VERSION 5.8 ;
BUSBITCHARS "[]" ;
DIVIDERCHAR "/" ;
UNITS
    DATABASE MICRONS 1000 ;
END UNITS

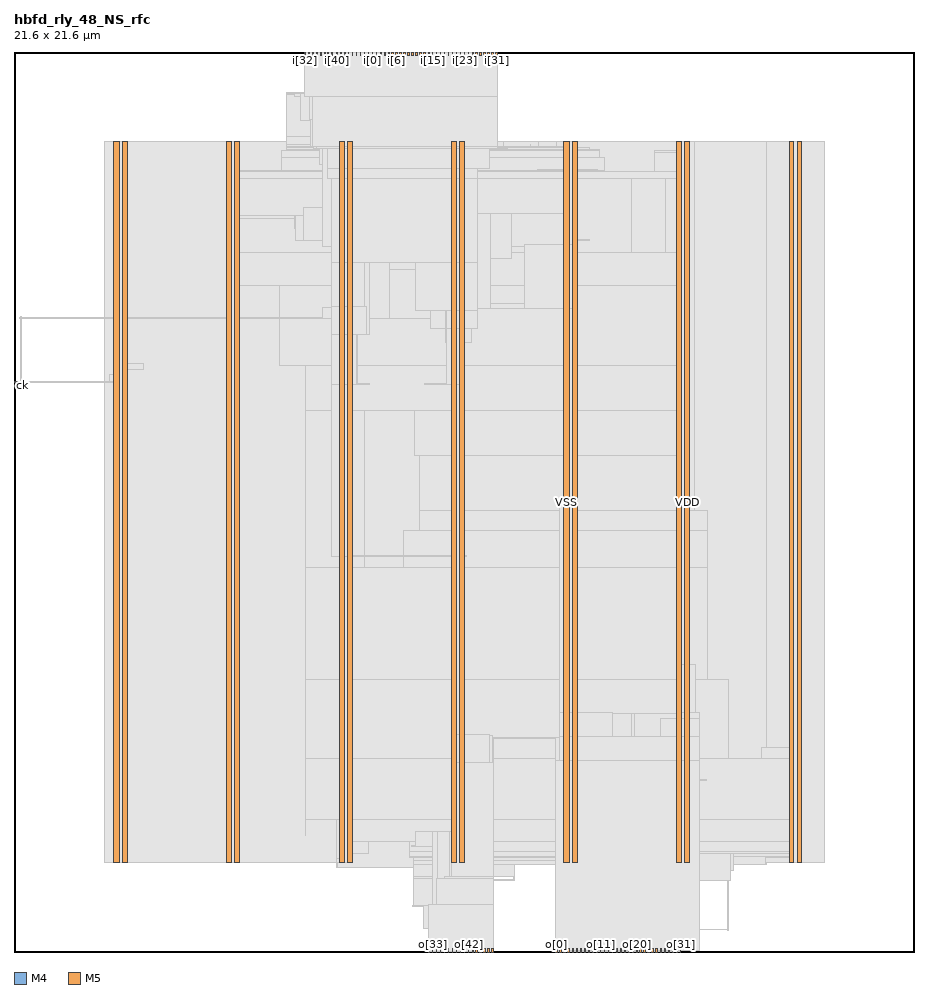
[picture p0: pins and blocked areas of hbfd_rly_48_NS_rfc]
MACRO hbfd_rly_48_NS_rfc
  FOREIGN hbfd_rly_48_NS_rfc 0 0 ;
  CLASS BLOCK ;
  SIZE 21.6 BY 21.6 ;
  PIN ck
    DIRECTION INPUT ;
    USE SIGNAL ;
    PORT
      LAYER M4 ;
        RECT  0 13.584 0.084 13.608 ;
    END
  END ck
  PIN i[0]
    DIRECTION INPUT ;
    USE SIGNAL ;
    PORT
      LAYER M5 ;
        RECT  8.592 21.516 8.616 21.6 ;
    END
  END i[0]
  PIN i[10]
    DIRECTION INPUT ;
    USE SIGNAL ;
    PORT
      LAYER M5 ;
        RECT  9.552 21.516 9.576 21.6 ;
    END
  END i[10]
  PIN i[11]
    DIRECTION INPUT ;
    USE SIGNAL ;
    PORT
      LAYER M5 ;
        RECT  9.648 21.516 9.672 21.6 ;
    END
  END i[11]
  PIN i[12]
    DIRECTION INPUT ;
    USE SIGNAL ;
    PORT
      LAYER M5 ;
        RECT  9.744 21.516 9.768 21.6 ;
    END
  END i[12]
  PIN i[13]
    DIRECTION INPUT ;
    USE SIGNAL ;
    PORT
      LAYER M5 ;
        RECT  9.84 21.516 9.864 21.6 ;
    END
  END i[13]
  PIN i[14]
    DIRECTION INPUT ;
    USE SIGNAL ;
    PORT
      LAYER M5 ;
        RECT  9.936 21.516 9.96 21.6 ;
    END
  END i[14]
  PIN i[15]
    DIRECTION INPUT ;
    USE SIGNAL ;
    PORT
      LAYER M5 ;
        RECT  10.032 21.516 10.056 21.6 ;
    END
  END i[15]
  PIN i[16]
    DIRECTION INPUT ;
    USE SIGNAL ;
    PORT
      LAYER M5 ;
        RECT  10.128 21.516 10.152 21.6 ;
    END
  END i[16]
  PIN i[17]
    DIRECTION INPUT ;
    USE SIGNAL ;
    PORT
      LAYER M5 ;
        RECT  10.224 21.516 10.248 21.6 ;
    END
  END i[17]
  PIN i[18]
    DIRECTION INPUT ;
    USE SIGNAL ;
    PORT
      LAYER M5 ;
        RECT  10.32 21.516 10.344 21.6 ;
    END
  END i[18]
  PIN i[19]
    DIRECTION INPUT ;
    USE SIGNAL ;
    PORT
      LAYER M5 ;
        RECT  10.416 21.516 10.44 21.6 ;
    END
  END i[19]
  PIN i[1]
    DIRECTION INPUT ;
    USE SIGNAL ;
    PORT
      LAYER M5 ;
        RECT  8.688 21.516 8.712 21.6 ;
    END
  END i[1]
  PIN i[20]
    DIRECTION INPUT ;
    USE SIGNAL ;
    PORT
      LAYER M5 ;
        RECT  10.512 21.516 10.536 21.6 ;
    END
  END i[20]
  PIN i[21]
    DIRECTION INPUT ;
    USE SIGNAL ;
    PORT
      LAYER M5 ;
        RECT  10.608 21.516 10.632 21.6 ;
    END
  END i[21]
  PIN i[22]
    DIRECTION INPUT ;
    USE SIGNAL ;
    PORT
      LAYER M5 ;
        RECT  10.704 21.516 10.728 21.6 ;
    END
  END i[22]
  PIN i[23]
    DIRECTION INPUT ;
    USE SIGNAL ;
    PORT
      LAYER M5 ;
        RECT  10.8 21.516 10.824 21.6 ;
    END
  END i[23]
  PIN i[24]
    DIRECTION INPUT ;
    USE SIGNAL ;
    PORT
      LAYER M5 ;
        RECT  10.896 21.516 10.92 21.6 ;
    END
  END i[24]
  PIN i[25]
    DIRECTION INPUT ;
    USE SIGNAL ;
    PORT
      LAYER M5 ;
        RECT  10.992 21.516 11.016 21.6 ;
    END
  END i[25]
  PIN i[26]
    DIRECTION INPUT ;
    USE SIGNAL ;
    PORT
      LAYER M5 ;
        RECT  11.088 21.516 11.112 21.6 ;
    END
  END i[26]
  PIN i[27]
    DIRECTION INPUT ;
    USE SIGNAL ;
    PORT
      LAYER M5 ;
        RECT  11.184 21.516 11.208 21.6 ;
    END
  END i[27]
  PIN i[28]
    DIRECTION INPUT ;
    USE SIGNAL ;
    PORT
      LAYER M5 ;
        RECT  11.28 21.516 11.304 21.6 ;
    END
  END i[28]
  PIN i[29]
    DIRECTION INPUT ;
    USE SIGNAL ;
    PORT
      LAYER M5 ;
        RECT  11.376 21.516 11.4 21.6 ;
    END
  END i[29]
  PIN i[2]
    DIRECTION INPUT ;
    USE SIGNAL ;
    PORT
      LAYER M5 ;
        RECT  8.784 21.516 8.808 21.6 ;
    END
  END i[2]
  PIN i[30]
    DIRECTION INPUT ;
    USE SIGNAL ;
    PORT
      LAYER M5 ;
        RECT  11.472 21.516 11.496 21.6 ;
    END
  END i[30]
  PIN i[31]
    DIRECTION INPUT ;
    USE SIGNAL ;
    PORT
      LAYER M5 ;
        RECT  11.568 21.516 11.592 21.6 ;
    END
  END i[31]
  PIN i[32]
    DIRECTION INPUT ;
    USE SIGNAL ;
    PORT
      LAYER M5 ;
        RECT  6.96 21.516 6.984 21.6 ;
    END
  END i[32]
  PIN i[33]
    DIRECTION INPUT ;
    USE SIGNAL ;
    PORT
      LAYER M5 ;
        RECT  7.056 21.516 7.08 21.6 ;
    END
  END i[33]
  PIN i[34]
    DIRECTION INPUT ;
    USE SIGNAL ;
    PORT
      LAYER M5 ;
        RECT  7.152 21.516 7.176 21.6 ;
    END
  END i[34]
  PIN i[35]
    DIRECTION INPUT ;
    USE SIGNAL ;
    PORT
      LAYER M5 ;
        RECT  7.248 21.516 7.272 21.6 ;
    END
  END i[35]
  PIN i[36]
    DIRECTION INPUT ;
    USE SIGNAL ;
    PORT
      LAYER M5 ;
        RECT  7.344 21.516 7.368 21.6 ;
    END
  END i[36]
  PIN i[37]
    DIRECTION INPUT ;
    USE SIGNAL ;
    PORT
      LAYER M5 ;
        RECT  7.44 21.516 7.464 21.6 ;
    END
  END i[37]
  PIN i[38]
    DIRECTION INPUT ;
    USE SIGNAL ;
    PORT
      LAYER M5 ;
        RECT  7.536 21.516 7.56 21.6 ;
    END
  END i[38]
  PIN i[39]
    DIRECTION INPUT ;
    USE SIGNAL ;
    PORT
      LAYER M5 ;
        RECT  7.632 21.516 7.656 21.6 ;
    END
  END i[39]
  PIN i[3]
    DIRECTION INPUT ;
    USE SIGNAL ;
    PORT
      LAYER M5 ;
        RECT  8.88 21.516 8.904 21.6 ;
    END
  END i[3]
  PIN i[40]
    DIRECTION INPUT ;
    USE SIGNAL ;
    PORT
      LAYER M5 ;
        RECT  7.728 21.516 7.752 21.6 ;
    END
  END i[40]
  PIN i[41]
    DIRECTION INPUT ;
    USE SIGNAL ;
    PORT
      LAYER M5 ;
        RECT  7.824 21.516 7.848 21.6 ;
    END
  END i[41]
  PIN i[42]
    DIRECTION INPUT ;
    USE SIGNAL ;
    PORT
      LAYER M5 ;
        RECT  7.92 21.516 7.944 21.6 ;
    END
  END i[42]
  PIN i[43]
    DIRECTION INPUT ;
    USE SIGNAL ;
    PORT
      LAYER M5 ;
        RECT  8.016 21.516 8.04 21.6 ;
    END
  END i[43]
  PIN i[44]
    DIRECTION INPUT ;
    USE SIGNAL ;
    PORT
      LAYER M5 ;
        RECT  8.112 21.516 8.136 21.6 ;
    END
  END i[44]
  PIN i[45]
    DIRECTION INPUT ;
    USE SIGNAL ;
    PORT
      LAYER M5 ;
        RECT  8.208 21.516 8.232 21.6 ;
    END
  END i[45]
  PIN i[46]
    DIRECTION INPUT ;
    USE SIGNAL ;
    PORT
      LAYER M5 ;
        RECT  8.304 21.516 8.328 21.6 ;
    END
  END i[46]
  PIN i[47]
    DIRECTION INPUT ;
    USE SIGNAL ;
    PORT
      LAYER M5 ;
        RECT  8.4 21.516 8.424 21.6 ;
    END
  END i[47]
  PIN i[4]
    DIRECTION INPUT ;
    USE SIGNAL ;
    PORT
      LAYER M5 ;
        RECT  8.976 21.516 9 21.6 ;
    END
  END i[4]
  PIN i[5]
    DIRECTION INPUT ;
    USE SIGNAL ;
    PORT
      LAYER M5 ;
        RECT  9.072 21.516 9.096 21.6 ;
    END
  END i[5]
  PIN i[6]
    DIRECTION INPUT ;
    USE SIGNAL ;
    PORT
      LAYER M5 ;
        RECT  9.168 21.516 9.192 21.6 ;
    END
  END i[6]
  PIN i[7]
    DIRECTION INPUT ;
    USE SIGNAL ;
    PORT
      LAYER M5 ;
        RECT  9.264 21.516 9.288 21.6 ;
    END
  END i[7]
  PIN i[8]
    DIRECTION INPUT ;
    USE SIGNAL ;
    PORT
      LAYER M5 ;
        RECT  9.36 21.516 9.384 21.6 ;
    END
  END i[8]
  PIN i[9]
    DIRECTION INPUT ;
    USE SIGNAL ;
    PORT
      LAYER M5 ;
        RECT  9.456 21.516 9.48 21.6 ;
    END
  END i[9]
  PIN o[0]
    DIRECTION OUTPUT ;
    USE SIGNAL ;
    PORT
      LAYER M5 ;
        RECT  13.008 0 13.032 0.084 ;
    END
  END o[0]
  PIN o[10]
    DIRECTION OUTPUT ;
    USE SIGNAL ;
    PORT
      LAYER M5 ;
        RECT  13.968 0 13.992 0.084 ;
    END
  END o[10]
  PIN o[11]
    DIRECTION OUTPUT ;
    USE SIGNAL ;
    PORT
      LAYER M5 ;
        RECT  14.064 0 14.088 0.084 ;
    END
  END o[11]
  PIN o[12]
    DIRECTION OUTPUT ;
    USE SIGNAL ;
    PORT
      LAYER M5 ;
        RECT  14.16 0 14.184 0.084 ;
    END
  END o[12]
  PIN o[13]
    DIRECTION OUTPUT ;
    USE SIGNAL ;
    PORT
      LAYER M5 ;
        RECT  14.256 0 14.28 0.084 ;
    END
  END o[13]
  PIN o[14]
    DIRECTION OUTPUT ;
    USE SIGNAL ;
    PORT
      LAYER M5 ;
        RECT  14.352 0 14.376 0.084 ;
    END
  END o[14]
  PIN o[15]
    DIRECTION OUTPUT ;
    USE SIGNAL ;
    PORT
      LAYER M5 ;
        RECT  14.448 0 14.472 0.084 ;
    END
  END o[15]
  PIN o[16]
    DIRECTION OUTPUT ;
    USE SIGNAL ;
    PORT
      LAYER M5 ;
        RECT  14.544 0 14.568 0.084 ;
    END
  END o[16]
  PIN o[17]
    DIRECTION OUTPUT ;
    USE SIGNAL ;
    PORT
      LAYER M5 ;
        RECT  14.64 0 14.664 0.084 ;
    END
  END o[17]
  PIN o[18]
    DIRECTION OUTPUT ;
    USE SIGNAL ;
    PORT
      LAYER M5 ;
        RECT  14.736 0 14.76 0.084 ;
    END
  END o[18]
  PIN o[19]
    DIRECTION OUTPUT ;
    USE SIGNAL ;
    PORT
      LAYER M5 ;
        RECT  14.832 0 14.856 0.084 ;
    END
  END o[19]
  PIN o[1]
    DIRECTION OUTPUT ;
    USE SIGNAL ;
    PORT
      LAYER M5 ;
        RECT  13.104 0 13.128 0.084 ;
    END
  END o[1]
  PIN o[20]
    DIRECTION OUTPUT ;
    USE SIGNAL ;
    PORT
      LAYER M5 ;
        RECT  14.928 0 14.952 0.084 ;
    END
  END o[20]
  PIN o[21]
    DIRECTION OUTPUT ;
    USE SIGNAL ;
    PORT
      LAYER M5 ;
        RECT  15.024 0 15.048 0.084 ;
    END
  END o[21]
  PIN o[22]
    DIRECTION OUTPUT ;
    USE SIGNAL ;
    PORT
      LAYER M5 ;
        RECT  15.12 0 15.144 0.084 ;
    END
  END o[22]
  PIN o[23]
    DIRECTION OUTPUT ;
    USE SIGNAL ;
    PORT
      LAYER M5 ;
        RECT  15.216 0 15.24 0.084 ;
    END
  END o[23]
  PIN o[24]
    DIRECTION OUTPUT ;
    USE SIGNAL ;
    PORT
      LAYER M5 ;
        RECT  15.312 0 15.336 0.084 ;
    END
  END o[24]
  PIN o[25]
    DIRECTION OUTPUT ;
    USE SIGNAL ;
    PORT
      LAYER M5 ;
        RECT  15.408 0 15.432 0.084 ;
    END
  END o[25]
  PIN o[26]
    DIRECTION OUTPUT ;
    USE SIGNAL ;
    PORT
      LAYER M5 ;
        RECT  15.504 0 15.528 0.084 ;
    END
  END o[26]
  PIN o[27]
    DIRECTION OUTPUT ;
    USE SIGNAL ;
    PORT
      LAYER M5 ;
        RECT  15.6 0 15.624 0.084 ;
    END
  END o[27]
  PIN o[28]
    DIRECTION OUTPUT ;
    USE SIGNAL ;
    PORT
      LAYER M5 ;
        RECT  15.696 0 15.72 0.084 ;
    END
  END o[28]
  PIN o[29]
    DIRECTION OUTPUT ;
    USE SIGNAL ;
    PORT
      LAYER M5 ;
        RECT  15.792 0 15.816 0.084 ;
    END
  END o[29]
  PIN o[2]
    DIRECTION OUTPUT ;
    USE SIGNAL ;
    PORT
      LAYER M5 ;
        RECT  13.2 0 13.224 0.084 ;
    END
  END o[2]
  PIN o[30]
    DIRECTION OUTPUT ;
    USE SIGNAL ;
    PORT
      LAYER M5 ;
        RECT  15.888 0 15.912 0.084 ;
    END
  END o[30]
  PIN o[31]
    DIRECTION OUTPUT ;
    USE SIGNAL ;
    PORT
      LAYER M5 ;
        RECT  15.984 0 16.008 0.084 ;
    END
  END o[31]
  PIN o[32]
    DIRECTION OUTPUT ;
    USE SIGNAL ;
    PORT
      LAYER M5 ;
        RECT  9.936 0 9.96 0.084 ;
    END
  END o[32]
  PIN o[33]
    DIRECTION OUTPUT ;
    USE SIGNAL ;
    PORT
      LAYER M5 ;
        RECT  10.032 0 10.056 0.084 ;
    END
  END o[33]
  PIN o[34]
    DIRECTION OUTPUT ;
    USE SIGNAL ;
    PORT
      LAYER M5 ;
        RECT  10.128 0 10.152 0.084 ;
    END
  END o[34]
  PIN o[35]
    DIRECTION OUTPUT ;
    USE SIGNAL ;
    PORT
      LAYER M5 ;
        RECT  10.224 0 10.248 0.084 ;
    END
  END o[35]
  PIN o[36]
    DIRECTION OUTPUT ;
    USE SIGNAL ;
    PORT
      LAYER M5 ;
        RECT  10.32 0 10.344 0.084 ;
    END
  END o[36]
  PIN o[37]
    DIRECTION OUTPUT ;
    USE SIGNAL ;
    PORT
      LAYER M5 ;
        RECT  10.416 0 10.44 0.084 ;
    END
  END o[37]
  PIN o[38]
    DIRECTION OUTPUT ;
    USE SIGNAL ;
    PORT
      LAYER M5 ;
        RECT  10.512 0 10.536 0.084 ;
    END
  END o[38]
  PIN o[39]
    DIRECTION OUTPUT ;
    USE SIGNAL ;
    PORT
      LAYER M5 ;
        RECT  10.608 0 10.632 0.084 ;
    END
  END o[39]
  PIN o[3]
    DIRECTION OUTPUT ;
    USE SIGNAL ;
    PORT
      LAYER M5 ;
        RECT  13.296 0 13.32 0.084 ;
    END
  END o[3]
  PIN o[40]
    DIRECTION OUTPUT ;
    USE SIGNAL ;
    PORT
      LAYER M5 ;
        RECT  10.704 0 10.728 0.084 ;
    END
  END o[40]
  PIN o[41]
    DIRECTION OUTPUT ;
    USE SIGNAL ;
    PORT
      LAYER M5 ;
        RECT  10.8 0 10.824 0.084 ;
    END
  END o[41]
  PIN o[42]
    DIRECTION OUTPUT ;
    USE SIGNAL ;
    PORT
      LAYER M5 ;
        RECT  10.896 0 10.92 0.084 ;
    END
  END o[42]
  PIN o[43]
    DIRECTION OUTPUT ;
    USE SIGNAL ;
    PORT
      LAYER M5 ;
        RECT  10.992 0 11.016 0.084 ;
    END
  END o[43]
  PIN o[44]
    DIRECTION OUTPUT ;
    USE SIGNAL ;
    PORT
      LAYER M5 ;
        RECT  11.088 0 11.112 0.084 ;
    END
  END o[44]
  PIN o[45]
    DIRECTION OUTPUT ;
    USE SIGNAL ;
    PORT
      LAYER M5 ;
        RECT  11.184 0 11.208 0.084 ;
    END
  END o[45]
  PIN o[46]
    DIRECTION OUTPUT ;
    USE SIGNAL ;
    PORT
      LAYER M5 ;
        RECT  11.28 0 11.304 0.084 ;
    END
  END o[46]
  PIN o[47]
    DIRECTION OUTPUT ;
    USE SIGNAL ;
    PORT
      LAYER M5 ;
        RECT  11.376 0 11.4 0.084 ;
    END
  END o[47]
  PIN o[4]
    DIRECTION OUTPUT ;
    USE SIGNAL ;
    PORT
      LAYER M5 ;
        RECT  13.392 0 13.416 0.084 ;
    END
  END o[4]
  PIN o[5]
    DIRECTION OUTPUT ;
    USE SIGNAL ;
    PORT
      LAYER M5 ;
        RECT  13.488 0 13.512 0.084 ;
    END
  END o[5]
  PIN o[6]
    DIRECTION OUTPUT ;
    USE SIGNAL ;
    PORT
      LAYER M5 ;
        RECT  13.584 0 13.608 0.084 ;
    END
  END o[6]
  PIN o[7]
    DIRECTION OUTPUT ;
    USE SIGNAL ;
    PORT
      LAYER M5 ;
        RECT  13.68 0 13.704 0.084 ;
    END
  END o[7]
  PIN o[8]
    DIRECTION OUTPUT ;
    USE SIGNAL ;
    PORT
      LAYER M5 ;
        RECT  13.776 0 13.8 0.084 ;
    END
  END o[8]
  PIN o[9]
    DIRECTION OUTPUT ;
    USE SIGNAL ;
    PORT
      LAYER M5 ;
        RECT  13.872 0 13.896 0.084 ;
    END
  END o[9]
  PIN rfi
    DIRECTION INPUT ;
    USE SIGNAL ;
    PORT
      LAYER M5 ;
        RECT  8.496 21.516 8.52 21.6 ;
    END
  END rfi
  PIN rfo
    DIRECTION OUTPUT ;
    USE SIGNAL ;
    PORT
      LAYER M5 ;
        RECT  11.472 0 11.496 0.084 ;
    END
  END rfo
  PIN rs
    DIRECTION INPUT ;
    USE SIGNAL ;
    PORT
      LAYER M4 ;
        RECT  0 13.68 0.084 13.704 ;
    END
  END rs
  PIN VDD
    DIRECTION INOUT ;
    USE POWER ;
    PORT
      LAYER M5 ;
        RECT  18.792 2.151 18.912 19.449 ;
        RECT  16.092 2.151 16.212 19.449 ;
        RECT  13.392 2.151 13.512 19.449 ;
        RECT  10.692 2.151 10.812 19.449 ;
        RECT  7.992 2.151 8.112 19.449 ;
        RECT  5.292 2.151 5.412 19.449 ;
        RECT  2.592 2.151 2.712 19.449 ;
    END
  END VDD
  PIN VSS
    DIRECTION INOUT ;
    USE GROUND ;
    PORT
      LAYER M5 ;
        RECT  18.6 2.137 18.72 19.463 ;
        RECT  15.9 2.137 16.02 19.463 ;
        RECT  13.2 2.137 13.32 19.463 ;
        RECT  10.5 2.137 10.62 19.463 ;
        RECT  7.8 2.137 7.92 19.463 ;
        RECT  5.1 2.137 5.22 19.463 ;
        RECT  2.4 2.137 2.52 19.463 ;
    END
  END VSS
  OBS
    LAYER RVTN ;
     RECT  2.16 2.16 19.44 2.295 ;
     RECT  2.16 2.565 19.44 2.835 ;
     RECT  2.16 3.105 19.44 3.375 ;
     RECT  2.16 3.645 19.44 3.915 ;
     RECT  2.16 4.185 19.44 4.455 ;
     RECT  2.16 4.725 19.44 4.995 ;
     RECT  2.16 5.265 19.44 5.535 ;
     RECT  2.16 5.805 19.44 6.075 ;
     RECT  2.16 6.345 19.44 6.615 ;
     RECT  2.16 6.885 19.44 7.155 ;
     RECT  2.16 7.425 19.44 7.695 ;
     RECT  2.16 7.965 19.44 8.235 ;
     RECT  2.16 8.505 19.44 8.775 ;
     RECT  2.16 9.045 19.44 9.315 ;
     RECT  2.16 9.585 19.44 9.855 ;
     RECT  2.16 10.125 19.44 10.395 ;
     RECT  2.16 10.665 19.44 10.935 ;
     RECT  2.16 11.205 19.44 11.475 ;
     RECT  2.16 11.745 19.44 12.015 ;
     RECT  2.16 12.285 19.44 12.555 ;
     RECT  2.16 12.825 19.44 13.095 ;
     RECT  2.16 13.365 19.44 13.635 ;
     RECT  2.16 13.905 19.44 14.175 ;
     RECT  2.16 14.445 19.44 14.715 ;
     RECT  2.16 14.985 19.44 15.255 ;
     RECT  2.16 15.525 19.44 15.795 ;
     RECT  2.16 16.065 19.44 16.335 ;
     RECT  2.16 16.605 19.44 16.875 ;
     RECT  2.16 17.145 19.44 17.415 ;
     RECT  2.16 17.685 19.44 17.955 ;
     RECT  2.16 18.225 19.44 18.495 ;
     RECT  2.16 18.765 19.44 19.035 ;
     RECT  2.16 19.305 19.44 19.44 ;
    LAYER RVTP ;
     RECT  2.16 2.295 19.44 2.565 ;
     RECT  2.16 2.835 19.44 3.105 ;
     RECT  2.16 3.375 19.44 3.645 ;
     RECT  2.16 3.915 19.44 4.185 ;
     RECT  2.16 4.455 19.44 4.725 ;
     RECT  2.16 4.995 19.44 5.265 ;
     RECT  2.16 5.535 19.44 5.805 ;
     RECT  2.16 6.075 19.44 6.345 ;
     RECT  2.16 6.615 19.44 6.885 ;
     RECT  2.16 7.155 19.44 7.425 ;
     RECT  2.16 7.695 19.44 7.965 ;
     RECT  2.16 8.235 19.44 8.505 ;
     RECT  2.16 8.775 19.44 9.045 ;
     RECT  2.16 9.315 19.44 9.585 ;
     RECT  2.16 9.855 19.44 10.125 ;
     RECT  2.16 10.395 19.44 10.665 ;
     RECT  2.16 10.935 19.44 11.205 ;
     RECT  2.16 11.475 19.44 11.745 ;
     RECT  2.16 12.015 19.44 12.285 ;
     RECT  2.16 12.555 19.44 12.825 ;
     RECT  2.16 13.095 19.44 13.365 ;
     RECT  2.16 13.635 19.44 13.905 ;
     RECT  2.16 14.175 19.44 14.445 ;
     RECT  2.16 14.715 19.44 14.985 ;
     RECT  2.16 15.255 19.44 15.525 ;
     RECT  2.16 15.795 19.44 16.065 ;
     RECT  2.16 16.335 19.44 16.605 ;
     RECT  2.16 16.875 19.44 17.145 ;
     RECT  2.16 17.415 19.44 17.685 ;
     RECT  2.16 17.955 19.44 18.225 ;
     RECT  2.16 18.495 19.44 18.765 ;
     RECT  2.16 19.035 19.44 19.305 ;
    LAYER M1 ;
     RECT  2.16 2.151 19.44 19.449 ;
    LAYER M2 ;
     RECT  2.16 2.151 7.735 19.449 ;
     RECT  10.075 1.152 10.211 1.17 ;
     RECT  7.735 2.034 10.427 19.449 ;
     RECT  10.427 2.106 11.759 19.449 ;
     RECT  11.759 2.151 12.595 19.449 ;
     RECT  12.595 2.106 13.019 19.449 ;
     RECT  13.783 0.036 14.467 0.054 ;
     RECT  14.467 0.036 14.935 0.126 ;
     RECT  14.935 0.036 16.043 0.549 ;
     RECT  13.019 2.151 16.339 19.449 ;
     RECT  16.043 0.531 17.159 0.549 ;
     RECT  16.339 2.106 18.059 19.449 ;
     RECT  18.059 2.151 19.44 19.449 ;
    LAYER M3 ;
     RECT  16.02 0.031 16.038 0.077 ;
     RECT  13.788 0.031 13.806 0.091 ;
     RECT  13.788 0.091 14.49 0.125 ;
     RECT  14.472 0.125 14.49 0.131 ;
     RECT  15.984 0.103 16.002 0.173 ;
     RECT  15.696 0.187 15.714 0.235 ;
     RECT  14.724 0.139 14.742 0.52 ;
     RECT  15.516 0.235 15.714 0.52 ;
     RECT  10.656 0.091 10.674 0.523 ;
     RECT  10.224 0.523 10.674 0.571 ;
     RECT  9.828 0.571 10.674 1.099 ;
     RECT  13.356 1.147 13.374 1.723 ;
     RECT  17.136 0.526 17.154 1.723 ;
     RECT  9.576 1.099 10.674 1.771 ;
     RECT  17.136 1.723 17.19 1.771 ;
     RECT  9.576 1.771 11.214 1.819 ;
     RECT  11.988 1.723 12.006 1.819 ;
     RECT  16.524 1.771 17.19 1.963 ;
     RECT  13.356 1.723 13.878 2.011 ;
     RECT  9.576 1.819 12.006 2.101 ;
     RECT  13.068 2.011 13.878 2.101 ;
     RECT  14.724 0.52 15.714 2.101 ;
     RECT  16.524 1.963 17.262 2.101 ;
     RECT  7.74 2.029 7.758 2.143 ;
     RECT  18.036 2.101 18.054 2.143 ;
     RECT  9.576 2.101 13.878 2.191 ;
     RECT  14.724 2.101 17.262 2.191 ;
     RECT  7.74 2.143 7.905 2.255 ;
     RECT  9.576 2.191 17.262 2.263 ;
     RECT  18.036 2.143 18.705 2.263 ;
     RECT  9.504 2.263 17.262 2.299 ;
     RECT  18.036 2.263 18.738 2.299 ;
     RECT  7.815 2.255 7.905 2.371 ;
     RECT  2.415 2.143 2.505 2.413 ;
     RECT  5.115 2.143 5.205 2.413 ;
     RECT  9.504 2.299 18.738 2.413 ;
     RECT  7.815 2.371 8.514 2.641 ;
     RECT  9.504 2.413 18.897 2.641 ;
     RECT  6.984 2.803 7.002 3.181 ;
     RECT  7.815 2.641 18.897 3.181 ;
     RECT  6.984 3.181 18.897 4.649 ;
     RECT  17.928 4.649 18.897 4.919 ;
     RECT  6.984 4.649 17.154 6.539 ;
     RECT  6.984 6.539 16.65 9.239 ;
     RECT  9.36 9.239 16.65 10.121 ;
     RECT  9.72 10.121 16.65 10.589 ;
     RECT  9.72 10.589 16.197 11.911 ;
     RECT  6.984 9.239 8.406 12.991 ;
     RECT  9.612 11.911 16.197 12.991 ;
     RECT  2.415 2.413 2.697 13.675 ;
     RECT  2.304 13.675 2.697 13.865 ;
     RECT  2.415 13.865 2.697 13.981 ;
     RECT  6.984 12.991 16.197 14.071 ;
     RECT  2.415 13.981 3.114 14.135 ;
     RECT  5.115 2.413 5.397 15.997 ;
     RECT  6.372 14.071 16.197 15.997 ;
     RECT  5.115 15.997 16.197 16.799 ;
     RECT  5.115 16.799 14.814 18.571 ;
     RECT  15.624 16.799 16.197 18.571 ;
     RECT  5.115 18.571 16.197 18.725 ;
     RECT  5.115 18.725 14.166 18.761 ;
     RECT  6.408 18.761 14.166 19.067 ;
     RECT  2.415 14.135 2.697 19.187 ;
     RECT  5.115 18.761 5.397 19.187 ;
     RECT  15.372 18.725 16.197 19.187 ;
     RECT  18.615 4.919 18.897 19.187 ;
     RECT  6.408 19.067 14.058 19.229 ;
     RECT  15.372 19.187 16.005 19.229 ;
     RECT  6.552 19.229 14.058 19.265 ;
     RECT  6.552 19.265 13.806 19.301 ;
     RECT  6.552 19.301 13.305 19.337 ;
     RECT  6.552 19.337 11.538 19.373 ;
     RECT  12.384 19.337 12.402 19.373 ;
     RECT  2.415 19.187 2.505 19.457 ;
     RECT  5.115 19.187 5.205 19.457 ;
     RECT  10.332 19.373 11.25 19.457 ;
     RECT  13.215 19.337 13.305 19.457 ;
     RECT  15.915 19.229 16.005 19.457 ;
     RECT  18.615 19.187 18.705 19.457 ;
     RECT  6.552 19.373 8.334 19.565 ;
     RECT  10.332 19.457 10.422 19.565 ;
     RECT  10.332 19.565 10.35 19.613 ;
     RECT  8.28 19.565 8.334 19.997 ;
     RECT  9.072 19.373 9.09 19.997 ;
     RECT  8.28 19.997 8.298 20.573 ;
     RECT  6.552 19.565 7.29 20.621 ;
     RECT  11.232 19.457 11.25 21.437 ;
     RECT  7.272 20.621 7.29 21.485 ;
     RECT  8.316 21.259 8.334 21.485 ;
    LAYER M4 ;
     RECT  0.06 13.584 0.179 13.704 ;
     RECT  0.179 13.68 2.408 13.704 ;
     RECT  0.133 15.216 2.408 15.24 ;
     RECT  2.408 2.148 2.512 19.452 ;
     RECT  2.512 2.418 2.704 19.182 ;
     RECT  2.704 15.216 5.108 15.24 ;
     RECT  5.108 2.148 5.212 19.452 ;
     RECT  5.212 2.418 5.404 19.182 ;
     RECT  5.404 17.616 6.721 17.688 ;
     RECT  6.541 20.592 6.721 20.616 ;
     RECT  6.721 17.376 6.757 17.688 ;
     RECT  6.721 20.544 6.865 20.616 ;
     RECT  6.757 17.088 6.937 17.688 ;
     RECT  6.865 19.968 7.091 20.616 ;
     RECT  7.091 19.968 7.109 19.992 ;
     RECT  7.109 19.344 7.192 19.992 ;
     RECT  7.192 19.296 7.333 19.992 ;
     RECT  5.404 15.216 7.405 15.24 ;
     RECT  6.937 17.088 7.405 17.88 ;
     RECT  7.333 18.912 7.405 19.992 ;
     RECT  7.405 15.216 7.729 15.48 ;
     RECT  7.621 9.504 7.808 9.528 ;
     RECT  7.729 15.216 7.808 15.576 ;
     RECT  7.405 16.944 7.808 19.992 ;
     RECT  7.808 2.148 7.912 19.992 ;
     RECT  7.261 21.408 8.101 21.48 ;
     RECT  7.912 2.418 8.104 19.992 ;
     RECT  8.104 13.632 8.245 17.736 ;
     RECT  8.104 18.816 8.269 19.992 ;
     RECT  8.101 21.264 8.269 21.48 ;
     RECT  8.269 18.816 8.345 21.48 ;
     RECT  8.345 18.816 8.387 21.288 ;
     RECT  8.245 14.832 8.524 17.736 ;
     RECT  8.245 13.632 8.525 13.656 ;
     RECT  8.387 18.816 8.627 20.568 ;
     RECT  8.524 15.216 9.011 17.736 ;
     RECT  8.627 18.816 9.097 19.992 ;
     RECT  9.097 18.768 9.203 19.992 ;
     RECT  9.349 21.216 9.587 21.432 ;
     RECT  9.529 2.544 9.637 2.568 ;
     RECT  9.011 17.472 9.745 17.736 ;
     RECT  9.203 18.768 9.745 19.368 ;
     RECT  9.565 1.104 9.817 1.128 ;
     RECT  9.011 15.216 9.997 16.392 ;
     RECT  9.817 0.576 10.033 1.128 ;
     RECT  9.637 2.544 10.033 2.904 ;
     RECT  10.033 0.576 10.172 2.904 ;
     RECT  9.745 17.472 10.321 19.368 ;
     RECT  9.997 14.976 10.357 16.392 ;
     RECT  10.172 0.528 10.451 2.904 ;
     RECT  10.451 1.728 10.508 2.904 ;
     RECT  8.104 9.504 10.508 9.528 ;
     RECT  9.853 13.632 10.508 13.656 ;
     RECT  10.357 14.64 10.508 16.392 ;
     RECT  10.321 17.472 10.508 19.608 ;
     RECT  10.451 0.528 10.547 0.552 ;
     RECT  9.587 21.36 10.643 21.432 ;
     RECT  10.597 0.096 10.685 0.12 ;
     RECT  10.508 1.728 10.739 19.608 ;
     RECT  10.739 1.728 10.804 19.368 ;
     RECT  10.804 9.504 10.865 9.528 ;
     RECT  10.804 14.64 10.973 19.368 ;
     RECT  10.973 14.976 11.081 19.368 ;
     RECT  10.804 1.728 11.117 3.432 ;
     RECT  11.117 1.728 11.123 2.904 ;
     RECT  11.081 14.976 11.123 17.736 ;
     RECT  11.123 2.832 11.153 2.904 ;
     RECT  10.643 21.408 11.261 21.432 ;
     RECT  11.123 1.728 11.369 1.848 ;
     RECT  11.153 2.88 11.405 2.904 ;
     RECT  11.081 18.816 11.411 19.368 ;
     RECT  11.123 15.456 11.441 17.736 ;
     RECT  10.804 4.512 11.477 5.208 ;
     RECT  11.477 4.512 11.507 5.16 ;
     RECT  11.411 19.296 11.549 19.368 ;
     RECT  11.549 19.296 11.837 19.32 ;
     RECT  11.441 16.656 11.945 17.736 ;
     RECT  11.369 1.728 12.017 1.752 ;
     RECT  11.507 5.136 12.997 5.16 ;
     RECT  13.057 2.016 13.093 2.04 ;
     RECT  12.997 4.56 13.129 5.16 ;
     RECT  13.093 2.016 13.208 2.28 ;
     RECT  13.129 3.84 13.208 5.16 ;
     RECT  13.052 10.848 13.208 10.872 ;
     RECT  11.441 15.456 13.208 15.576 ;
     RECT  11.945 16.944 13.208 17.736 ;
     RECT  12.553 18.768 13.208 18.792 ;
     RECT  13.093 0.24 13.285 0.264 ;
     RECT  13.208 2.016 13.285 19.452 ;
     RECT  13.285 0.24 13.312 19.452 ;
     RECT  13.312 0.24 13.385 19.182 ;
     RECT  13.385 1.728 13.504 19.182 ;
     RECT  13.385 0.24 13.573 0.456 ;
     RECT  13.573 0.144 13.619 0.456 ;
     RECT  13.504 3.408 13.673 5.736 ;
     RECT  13.619 0.144 13.733 0.264 ;
     RECT  13.673 3.408 13.753 4.008 ;
     RECT  13.504 17.088 13.817 17.112 ;
     RECT  13.504 18.768 13.997 18.792 ;
     RECT  13.504 1.728 14.249 2.28 ;
     RECT  13.733 0.096 14.501 0.264 ;
     RECT  14.501 0.144 14.753 0.264 ;
     RECT  13.753 3.984 14.821 4.008 ;
     RECT  13.673 5.136 14.821 5.736 ;
     RECT  14.753 0.192 14.885 0.264 ;
     RECT  14.821 3.984 14.897 5.736 ;
     RECT  14.885 0.192 15.251 0.552 ;
     RECT  14.249 1.728 15.301 1.848 ;
     RECT  15.301 1.728 15.397 1.896 ;
     RECT  15.397 1.728 15.685 1.992 ;
     RECT  15.251 0.192 15.724 0.264 ;
     RECT  15.685 1.728 15.781 2.088 ;
     RECT  15.781 1.728 15.908 2.328 ;
     RECT  14.897 4.128 15.908 5.736 ;
     RECT  15.724 0.144 16.009 0.264 ;
     RECT  15.908 1.728 16.012 19.452 ;
     RECT  16.012 1.728 16.204 19.182 ;
     RECT  16.204 5.568 16.265 5.736 ;
     RECT  16.204 6.864 16.355 6.888 ;
     RECT  16.009 0.048 16.403 0.264 ;
     RECT  16.204 4.128 16.445 4.536 ;
     RECT  16.403 0.048 16.451 0.072 ;
     RECT  16.265 5.712 16.453 5.736 ;
     RECT  16.445 4.128 16.625 4.152 ;
     RECT  16.204 1.728 17.201 2.376 ;
     RECT  17.201 1.968 17.273 2.376 ;
     RECT  17.273 2.304 18.608 2.376 ;
     RECT  18.608 2.148 18.712 19.452 ;
     RECT  18.712 2.418 18.904 19.182 ;
    LAYER M5 ;
     RECT  13.008 0.016 16.008 0.037 ;
     RECT  9.936 0.016 11.496 1.139 ;
     RECT  10.128 1.139 11.496 1.763 ;
     RECT  10.32 1.763 11.496 1.811 ;
     RECT  2.4 2.137 2.52 2.151 ;
     RECT  5.1 2.137 5.22 2.151 ;
     RECT  7.8 2.137 7.92 2.151 ;
     RECT  18.6 2.137 18.72 2.151 ;
     RECT  10.5 1.811 11.496 4.547 ;
     RECT  13.008 0.037 16.44 4.595 ;
     RECT  13.104 4.595 16.44 5.171 ;
     RECT  10.5 4.547 11.4 5.219 ;
     RECT  15.504 5.171 16.44 5.603 ;
     RECT  13.104 5.171 14.376 5.747 ;
     RECT  15.9 5.603 16.44 5.747 ;
     RECT  15.9 5.747 16.344 6.899 ;
     RECT  7.8 2.151 8.112 9.493 ;
     RECT  13.104 5.747 13.512 10.883 ;
     RECT  7.632 9.493 8.112 13.621 ;
     RECT  10.5 5.219 10.812 13.621 ;
     RECT  7.632 13.621 8.232 14.821 ;
     RECT  10.368 13.621 10.812 14.965 ;
     RECT  0.144 13.573 0.168 15.251 ;
     RECT  10.368 14.965 11.112 15.397 ;
     RECT  13.2 10.883 13.512 15.445 ;
     RECT  7.632 14.821 8.472 15.491 ;
     RECT  7.632 15.491 8.424 16.549 ;
     RECT  9.648 15.397 11.112 16.549 ;
     RECT  12.24 15.445 13.512 16.979 ;
     RECT  7.632 16.549 11.112 18.565 ;
     RECT  7.536 18.565 11.112 18.805 ;
     RECT  7.536 18.805 11.4 19.285 ;
     RECT  7.248 19.285 11.592 19.333 ;
     RECT  2.4 2.151 2.712 19.449 ;
     RECT  5.1 2.151 5.412 19.449 ;
     RECT  13.2 16.979 13.512 19.449 ;
     RECT  15.9 6.899 16.212 19.449 ;
     RECT  18.6 2.151 18.912 19.449 ;
     RECT  2.4 19.449 2.52 19.463 ;
     RECT  5.1 19.449 5.22 19.463 ;
     RECT  13.2 19.449 13.32 19.463 ;
     RECT  15.9 19.449 16.02 19.463 ;
     RECT  18.6 19.449 18.72 19.463 ;
     RECT  7.152 19.333 11.592 20.533 ;
     RECT  6.96 20.533 11.592 21.584 ;
  END
END hbfd_rly_48_NS_rfc
END LIBRARY
